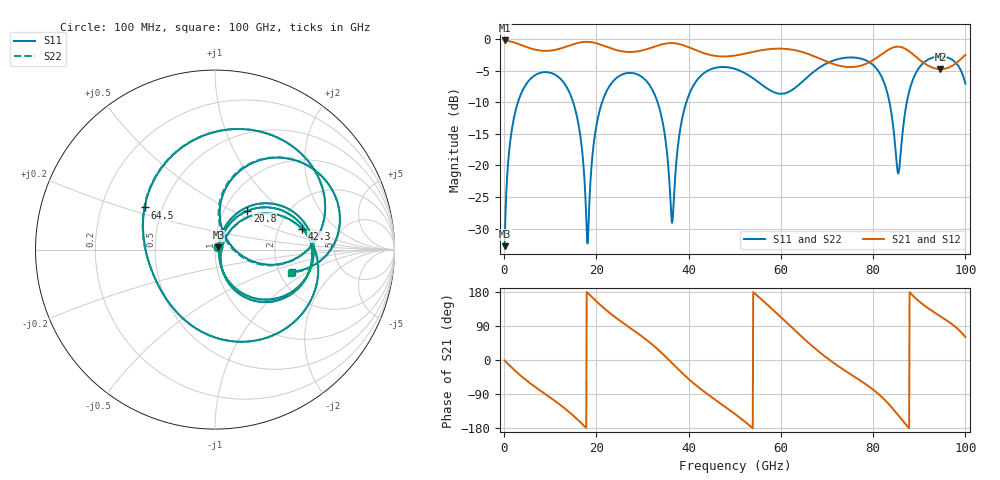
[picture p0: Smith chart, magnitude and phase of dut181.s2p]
! Touchstone file exported from HFSS 2026.1.0
!  File:  C:/ffzhzh/LocalFiles/Ansys_Project_Files/temp_test_TSV_RDL_181_1783476337_46308.aedt
!  Generated:  10:17:16 AM Jul  8, 2026
!  Design:  TSV_RDL
!  Project:  temp_test_TSV_RDL_181_1783476337_46308
! Variables:
!  h_bsmrdl = 4.29um
!  h_ox = 20um
!  h_rdl = 5um
!  h_sub = 81.41um
!  h_tmrdl = 2.25um
!  h_tsv = 81.41um
!  h_via = 3um
!  l_bsmrdl = 369.42um
!  l_sub = 3302.89um
!  l_tmrdl = 418.35um
!  m_sub = 200um
!  pitch = 52.11um
!  r_tsv = 8.42um
!  s_tmrdl = 10um
!  w_bsmrdl = 11.18um
!  w_sub = 500um
!  w_tmrdl = 29.23um
!  x_tsv_center1 = 432.965um
!  x_tsv_center2 = 813.565um
!  x_tsv_center3 = 1261.145um
!  x_tsv_center4 = 1641.745um
!  x_tsv_center5 = 2089.325um
!  x_tsv_center6 = 2469.925um
# GHz S MA R 50.000000
! Terminal data exported
! Port[1] = TM_RDL1_1_T1
! Port[2] = TM_RDL5_1_T1
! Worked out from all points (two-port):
!   1000 points, 100 MHz to 100 GHz, reference 50 ohm
!   highest |S21| = -0.17 dB at 100 MHz (marker M1); lowest = -4.7 dB at 94.6 GHz (marker M2)
!   |S21| within 3 dB of the highest: start of sweep to 68.79 GHz; 80.25 GHz to 89.95 GHz (9.705 GHz wide, 11.4 % of centre) (the widest 2 of 3)
!   lowest |S11| = -32.8 dB at 100 MHz (marker M3), VSWR 1.05, Z = 51.9 + j1.29 ohm
!   |S11| at or under -10 dB: 14.98 GHz to 21.22 GHz (6.248 GHz wide, 34.5 % of centre); 33.28 GHz to 39.49 GHz (6.207 GHz wide, 17.1 % of centre); 83.55 GHz to 87.29 GHz (3.742 GHz wide, 4.38 % of centre) (the widest 3 of 4)
!   |S22| runs from -32.8 to -2.7 dB; largest |S21 - S12| = 5.3e-14
!   S11 on the Smith chart (normalised r, x): 100 MHz: 1.04, +0.03; 20.8 GHz: 1.28, +0.60; 42.3 GHz: 2.70, +0.83; 64.5 GHz: 0.40, +0.24; 100 GHz: 2.35, -0.72
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0.1  0.02292 32.9  0.9809 -1.3  0.9809 -1.3  0.02292 32.9
! Gamma 0 0 0 0
! Port Impedance 50 0 50 0
1.9  0.2161 60.7  0.9519 -22.8  0.9519 -22.8  0.2161 60.7
5.7  0.486 25.3  0.8492 -62.0  0.8492 -62.0  0.486 25.3
12.9  0.4552 -35.4  0.8624 -125.4  0.8624 -125.4  0.4552 -35.4
16.8  0.1421 -69.7  0.9504 -167.4  0.9504 -167.4  0.1422 -69.7
18.1  0.02411 2.6  0.9565 177.1  0.9565 177.1  0.02404 2.4
20.8  0.2808 50.2  0.9123 145.8  0.9123 145.8  0.2808 50.1
27  0.5423 -3.7  0.7945 87.4  0.7945 87.4  0.5423 -3.8
33.4  0.3065 -58.7  0.896 27.1  0.896 27.1  0.3066 -58.6
36.4  0.03509 -12.3  0.9351 -8.1  0.9351 -8.1  0.03652 -12.4
38.7  0.2452 45.9  0.9026 -35.6  0.9026 -35.6  0.2454 45.3
42.3  0.4994 13.3  0.8011 -73.6  0.8011 -73.6  0.4995 13.0
50.1  0.5828 -52.6  0.7452 -143.0  0.7452 -143.0  0.5829 -52.8
56.6  0.4181 -117.2  0.8296 151.2  0.8296 151.2  0.4184 -116.9
64.5  0.4569 149.1  0.7968 61.7  0.7968 61.7  0.4566 150.2
66.7  0.538 124.8  0.7473 37.8  0.7473 37.8  0.5375 125.8
77.5  0.7016 34.2  0.6219 -56.6  0.6219 -56.6  0.701 34.4
83.4  0.3358 -14.5  0.8312 -116.6  0.8312 -116.6  0.3345 -15.2
85.5  0.08676 38.5  0.8759 -146.9  0.8759 -146.9  0.08072 39.1
88.6  0.4781 71.0  0.7631 170.0  0.7631 170.0  0.4771 71.7
94.6  0.7333 24.7  0.5809 115.2  0.5809 115.2  0.7327 24.8
100  0.4459 -15.9  0.7537 60.7  0.7537 60.7  0.444 -16.7
